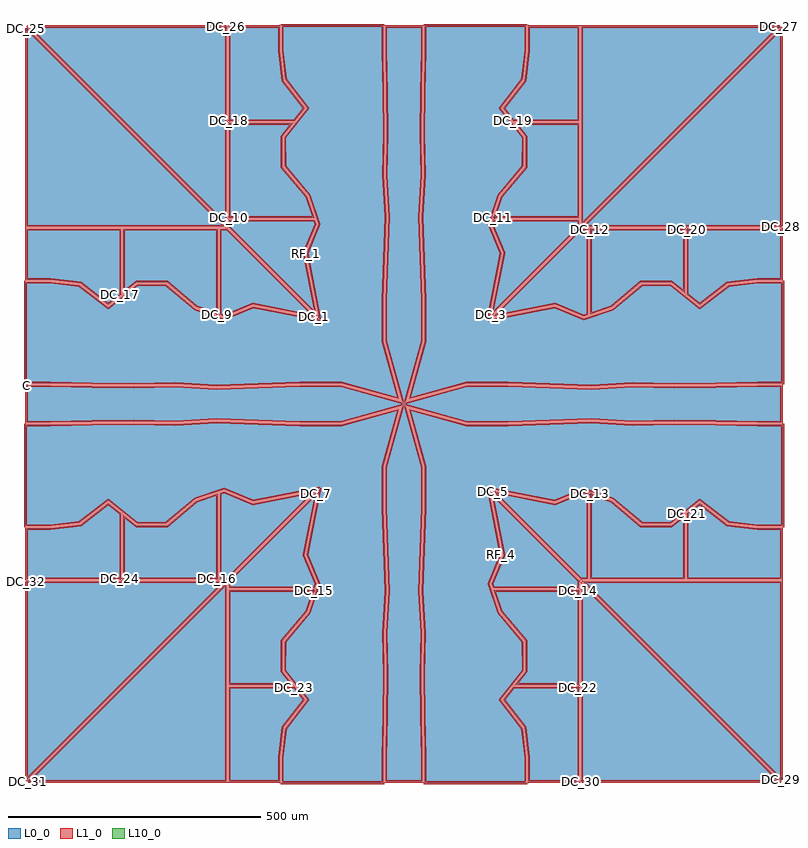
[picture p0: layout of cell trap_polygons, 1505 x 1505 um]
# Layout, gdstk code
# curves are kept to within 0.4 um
import gdstk
lib = gdstk.Library(unit=1e-6, precision=1e-09)
def P(c, l, *ps):  # polygons
    for p in ps: c.add(gdstk.Polygon(p, *l))
L0_0 = (0, 0)
L1_0 = (1, 0)
L10_0 = (10, 0)

trap_polygons = lib.new_cell('trap_polygons')
P(trap_polygons, L0_0, [(-747.5,-351.5),(-355.036,-351.5),(-747.5,-743.964),(-747.5,-351.5)],
  [(-743.964,-747.5),(-351.5,-355.036),(-351.5,-747.5),(-743.964,-747.5)],
  [(351.5,-747.5),(351.5,-355.036),(743.964,-747.5),(351.5,-747.5)],
  [(747.5,-743.964),(355.036,-351.5),(747.5,-351.5),(747.5,-743.964)],
  [(747.5,351.5),(355.036,351.5),(747.5,743.964),(747.5,351.5)],
  [(743.964,747.5),(351.5,355.036),(351.5,747.5),(743.964,747.5)],
  [(-351.5,747.5),(-351.5,355.036),(-743.964,747.5),(-351.5,747.5)],
  [(-747.5,743.964),(-355.036,351.5),(-747.5,351.5),(-747.5,743.964)],
  [(-560.758,-346.5),(-585.43,-346.5),(-640.552,-346.5),(-699.496,-346.5),(-747.5,-346.5),(-747.5,-246.5),(-699.496,-246.5),(-640.552,-239.492),(-585.43,-196.951),(-560.758,-216.68),(-560.758,-346.5)],
  [(-216.68,-560.758),(-196.951,-585.43),(-239.492,-640.552),(-246.5,-699.496),(-246.5,-747.5),(-346.5,-747.5),(-346.5,-699.496),(-346.5,-640.552),(-346.5,-585.43),(-346.5,-560.758),(-216.68,-560.758)],
  [(346.5,-560.758),(346.5,-585.43),(346.5,-640.552),(346.5,-699.496),(346.5,-747.5),(246.5,-747.5),(246.5,-699.496),(239.492,-640.552),(196.951,-585.43),(216.68,-560.758),(346.5,-560.758)],
  [(560.758,-216.68),(585.43,-196.951),(640.552,-239.492),(699.496,-246.5),(747.5,-246.5),(747.5,-346.5),(699.496,-346.5),(640.552,-346.5),(585.43,-346.5),(560.758,-346.5),(560.758,-216.68)],
  [(560.758,346.5),(585.43,346.5),(640.552,346.5),(699.496,346.5),(747.5,346.5),(747.5,246.5),(699.496,246.5),(640.552,239.492),(585.43,196.951),(560.758,216.68),(560.758,346.5)],
  [(216.68,560.758),(196.951,585.43),(239.492,640.552),(246.5,699.496),(246.5,747.5),(346.5,747.5),(346.5,699.496),(346.5,640.552),(346.5,585.43),(346.5,560.758),(216.68,560.758)],
  [(-346.5,560.758),(-346.5,585.43),(-346.5,640.552),(-346.5,699.496),(-346.5,747.5),(-246.5,747.5),(-246.5,699.496),(-239.492,640.552),(-196.951,585.43),(-216.68,560.758),(-346.5,560.758)],
  [(-560.758,216.68),(-585.43,196.951),(-640.552,239.492),(-699.496,246.5),(-747.5,246.5),(-747.5,346.5),(-699.496,346.5),(-640.552,346.5),(-585.43,346.5),(-560.758,346.5),(-560.758,216.68)],
  [(-369.015,-346.5),(-410.94,-346.5),(-468.92,-346.5),(-529.805,-346.5),(-555.758,-346.5),(-555.758,-220.679),(-529.805,-241.432),(-468.92,-241.136),(-410.94,-192.501),(-369.015,-178.208),(-369.015,-346.5)],
  [(-178.208,-369.015),(-192.501,-410.94),(-241.136,-468.92),(-241.432,-529.805),(-220.679,-555.758),(-346.5,-555.758),(-346.5,-529.805),(-346.5,-468.92),(-346.5,-410.94),(-346.5,-369.015),(-178.208,-369.015)],
  [(346.5,-369.015),(346.5,-410.94),(346.5,-468.92),(346.5,-529.805),(346.5,-555.758),(220.679,-555.758),(241.432,-529.805),(241.136,-468.92),(192.501,-410.94),(178.208,-369.015),(346.5,-369.015)],
  [(369.015,-178.208),(410.94,-192.501),(468.92,-241.136),(529.805,-241.432),(555.758,-220.679),(555.758,-346.5),(529.805,-346.5),(468.92,-346.5),(410.94,-346.5),(369.015,-346.5),(369.015,-178.208)],
  [(369.015,346.5),(410.94,346.5),(468.92,346.5),(529.805,346.5),(555.758,346.5),(555.758,220.679),(529.805,241.432),(468.92,241.136),(410.94,192.501),(369.015,178.208),(369.015,346.5)],
  [(178.208,369.015),(192.501,410.94),(241.136,468.92),(241.432,529.805),(220.679,555.758),(346.5,555.758),(346.5,529.805),(346.5,468.92),(346.5,410.94),(346.5,369.015),(178.208,369.015)],
  [(-346.5,369.015),(-346.5,410.94),(-346.5,468.92),(-346.5,529.805),(-346.5,555.758),(-220.679,555.758),(-241.432,529.805),(-241.136,468.92),(-192.501,410.94),(-178.208,369.015),(-346.5,369.015)],
  [(-369.015,178.208),(-410.94,192.501),(-468.92,241.136),(-529.805,241.432),(-555.758,220.679),(-555.758,346.5),(-529.805,346.5),(-468.92,346.5),(-410.94,346.5),(-369.015,346.5),(-369.015,178.208)],
  [(-350.036,-346.5),(-356.299,-346.5),(-364.015,-346.5),(-364.015,-176.503),(-356.299,-173.873),(-299.337,-197.523),(-177.273,-173.737),(-350.036,-346.5)],
  [(-173.737,-177.273),(-197.523,-299.337),(-173.873,-356.299),(-176.503,-364.015),(-346.5,-364.015),(-346.5,-356.299),(-346.5,-350.036),(-173.737,-177.273)],
  [(346.5,-350.036),(346.5,-356.299),(346.5,-364.015),(176.503,-364.015),(173.873,-356.299),(197.523,-299.337),(173.737,-177.273),(346.5,-350.036)],
  [(177.273,-173.737),(299.337,-197.523),(356.299,-173.873),(364.015,-176.503),(364.015,-346.5),(356.299,-346.5),(350.036,-346.5),(177.273,-173.737)],
  [(350.036,346.5),(356.299,346.5),(364.015,346.5),(364.015,176.503),(356.299,173.873),(299.337,197.523),(177.273,173.737),(350.036,346.5)],
  [(173.737,177.273),(197.523,299.337),(173.873,356.299),(176.503,364.015),(346.5,364.015),(346.5,356.299),(346.5,350.036),(173.737,177.273)],
  [(-346.5,350.036),(-346.5,356.299),(-346.5,364.015),(-176.503,364.015),(-173.873,356.299),(-197.523,299.337),(-173.737,177.273),(-346.5,350.036)],
  [(-177.273,173.737),(-299.337,197.523),(-356.299,173.873),(-364.015,176.503),(-364.015,346.5),(-356.299,346.5),(-350.036,346.5),(-177.273,173.737)],
  [(-747.5,36.5),(-700,36.5),(-535.361,33.673),(-453.158,35.298),(-370.806,30.519),(-206.032,36.5),(-124.492,36.5),(-2.831,2.831),(-36.5,124.492),(-36.5,206.032),(-30.519,370.806),(-35.298,453.158),(-33.673,535.361),(-36.5,700),(-36.5,747.5),(36.5,747.5),(36.5,700),(33.673,535.361),(35.298,453.158),(30.519,370.806),(36.5,206.032),(36.5,124.492),(2.831,2.831),(124.492,36.5),(206.032,36.5),(370.806,30.519),(453.158,35.298),(535.361,33.673),(700,36.5),(747.5,36.5),(747.5,-36.5),(700,-36.5),(535.361,-33.673),(453.158,-35.298),(370.806,-30.519),(206.032,-36.5),(124.492,-36.5),(2.831,-2.831),(36.5,-124.492),(36.5,-206.032),(30.519,-370.806),(35.298,-453.158),(33.673,-535.361),(36.5,-700),(36.5,-747.5),(-36.5,-747.5),(-36.5,-700),(-33.673,-535.361),(-35.298,-453.158),(-30.519,-370.806),(-36.5,-206.032),(-36.5,-124.492),(-2.831,-2.831),(-124.492,-36.5),(-206.032,-36.5),(-370.806,-30.519),(-453.158,-35.298),(-535.361,-33.673),(-700,-36.5),(-747.5,-36.5)],
  [(192.327,-298.812),(168.531,-356.125),(188.07,-413.437),(236.144,-470.75),(236.423,-528.062),(190.593,-585.375),(234.824,-642.687),(241.5,-700),(241.5,-750),(41.5,-750),(41.5,-700),(38.674,-535.375),(40.301,-453.062),(35.524,-370.75),(41.5,-206.125),(41.5,-123.812),(10.004,-10.004),(123.812,-41.5),(206.125,-41.5),(370.75,-35.524),(453.062,-40.301),(535.375,-38.674),(700,-41.5),(750,-41.5),(750,-241.5),(700,-241.5),(642.687,-234.824),(585.375,-190.593),(528.062,-236.423),(470.75,-236.144),(413.437,-188.07),(356.125,-168.531),(298.812,-192.327),(166.555,-166.555)],
  [(166.555,166.555),(298.812,192.327),(356.125,168.531),(413.437,188.07),(470.75,236.144),(528.062,236.423),(585.375,190.593),(642.687,234.824),(700,241.5),(750,241.5),(750,41.5),(700,41.5),(535.375,38.674),(453.062,40.301),(370.75,35.524),(206.125,41.5),(123.812,41.5),(10.004,10.004),(41.5,123.812),(41.5,206.125),(35.524,370.75),(40.301,453.062),(38.674,535.375),(41.5,700),(41.5,750),(241.5,750),(241.5,700),(234.824,642.687),(190.593,585.375),(236.423,528.062),(236.144,470.75),(188.07,413.437),(168.531,356.125),(192.327,298.812)],
  [(-166.555,-166.555),(-298.812,-192.327),(-356.125,-168.531),(-413.437,-188.07),(-470.75,-236.144),(-528.062,-236.423),(-585.375,-190.593),(-642.687,-234.824),(-700,-241.5),(-750,-241.5),(-750,-41.5),(-700,-41.5),(-535.375,-38.674),(-453.062,-40.301),(-370.75,-35.524),(-206.125,-41.5),(-123.812,-41.5),(-10.004,-10.004),(-41.5,-123.812),(-41.5,-206.125),(-35.524,-370.75),(-40.301,-453.062),(-38.674,-535.375),(-41.5,-700),(-41.5,-750),(-241.5,-750),(-241.5,-700),(-234.824,-642.687),(-190.593,-585.375),(-236.423,-528.062),(-236.144,-470.75),(-188.07,-413.437),(-168.531,-356.125),(-192.327,-298.812)],
  [(-192.327,298.812),(-168.531,356.125),(-188.07,413.437),(-236.144,470.75),(-236.423,528.062),(-190.593,585.375),(-234.824,642.687),(-241.5,700),(-241.5,750),(-41.5,750),(-41.5,700),(-38.674,535.375),(-40.301,453.062),(-35.524,370.75),(-41.5,206.125),(-41.5,123.812),(-10.004,10.004),(-123.812,41.5),(-206.125,41.5),(-370.75,35.524),(-453.062,40.301),(-535.375,38.674),(-700,41.5),(-750,41.5),(-750,241.5),(-700,241.5),(-642.687,234.824),(-585.375,190.593),(-528.062,236.423),(-470.75,236.144),(-413.437,188.07),(-356.125,168.531),(-298.812,192.327),(-166.555,166.555)])
P(trap_polygons, L1_0, [(-747.5,-349),(-747.5,-354),(-361.071,-354),(-745,-737.929),(-745,-351.5),(-750,-351.5),(-750,-746.464),(-747.5,-747.5),(-351.5,-351.5),(-352.536,-349)],
  [(-745.732,-745.732),(-742.197,-749.268),(-354,-361.071),(-354,-745),(-743.964,-745),(-743.964,-750),(-349,-750),(-349,-352.536),(-351.5,-351.5)],
  [(349,-747.5),(354,-747.5),(354,-361.071),(737.929,-745),(351.5,-745),(351.5,-750),(746.464,-750),(747.5,-747.5),(351.5,-351.5),(349,-352.536)],
  [(745.732,-745.732),(749.268,-742.197),(361.071,-354),(745,-354),(745,-743.964),(750,-743.964),(750,-349),(352.536,-349),(351.5,-351.5)],
  [(747.5,349),(747.5,354),(361.071,354),(745,737.929),(745,351.5),(750,351.5),(750,746.464),(747.5,747.5),(351.5,351.5),(352.536,349)],
  [(745.732,745.732),(742.197,749.268),(354,361.071),(354,745),(743.964,745),(743.964,750),(349,750),(349,352.536),(351.5,351.5)],
  [(-349,747.5),(-354,747.5),(-354,361.071),(-737.929,745),(-351.5,745),(-351.5,750),(-746.464,750),(-747.5,747.5),(-351.5,351.5),(-349,352.536)],
  [(-745.732,745.732),(-749.268,742.197),(-361.071,354),(-745,354),(-745,743.964),(-750,743.964),(-750,349),(-352.536,349),(-351.5,351.5)],
  [(-560.758,-349),(-560.758,-344),(-745,-344),(-745,-249),(-699.348,-249),(-639.571,-241.893),(-585.457,-200.13),(-563.258,-217.882),(-563.258,-346.5),(-558.258,-346.5),(-558.258,-215.478),(-585.402,-193.772),(-641.533,-237.091),(-699.644,-244),(-750,-244),(-750,-349)],
  [(-214.728,-559.196),(-218.633,-562.319),(-200.13,-585.457),(-241.893,-639.571),(-249,-699.348),(-249,-745),(-344,-745),(-344,-563.258),(-216.68,-563.258),(-216.68,-558.258),(-349,-558.258),(-349,-750),(-244,-750),(-244,-699.644),(-237.091,-641.533),(-193.772,-585.402)],
  [(349,-560.758),(344,-560.758),(344,-745),(249,-745),(249,-699.348),(241.893,-639.571),(200.13,-585.457),(217.882,-563.258),(346.5,-563.258),(346.5,-558.258),(215.478,-558.258),(193.772,-585.402),(237.091,-641.533),(244,-699.644),(244,-750),(349,-750)],
  [(559.196,-214.728),(562.319,-218.633),(585.457,-200.13),(639.571,-241.893),(699.348,-249),(745,-249),(745,-344),(563.258,-344),(563.258,-216.68),(558.258,-216.68),(558.258,-349),(750,-349),(750,-244),(699.644,-244),(641.533,-237.091),(585.402,-193.772)],
  [(560.758,349),(560.758,344),(745,344),(745,249),(699.348,249),(639.571,241.893),(585.457,200.13),(563.258,217.882),(563.258,346.5),(558.258,346.5),(558.258,215.478),(585.402,193.772),(641.533,237.091),(699.644,244),(750,244),(750,349)],
  [(214.728,559.196),(218.633,562.319),(200.13,585.457),(241.893,639.571),(249,699.348),(249,745),(344,745),(344,563.258),(216.68,563.258),(216.68,558.258),(349,558.258),(349,750),(244,750),(244,699.644),(237.091,641.533),(193.772,585.402)],
  [(-349,560.758),(-344,560.758),(-344,745),(-249,745),(-249,699.348),(-241.893,639.571),(-200.13,585.457),(-217.882,563.258),(-346.5,563.258),(-346.5,558.258),(-215.478,558.258),(-193.772,585.402),(-237.091,641.533),(-244,699.644),(-244,750),(-349,750)],
  [(-559.196,214.728),(-562.319,218.633),(-585.457,200.13),(-639.571,241.893),(-699.348,249),(-745,249),(-745,344),(-563.258,344),(-563.258,216.68),(-558.258,216.68),(-558.258,349),(-750,349),(-750,244),(-699.644,244),(-641.533,237.091),(-585.402,193.772)],
  [(-369.015,-349),(-369.015,-344),(-553.258,-344),(-553.258,-225.879),(-530.676,-243.936),(-468.005,-243.631),(-409.691,-194.717),(-371.515,-181.702),(-371.515,-346.5),(-366.515,-346.5),(-366.515,-175.708),(-367.456,-175.035),(-412.189,-190.286),(-469.835,-238.64),(-528.934,-238.927),(-556.149,-217.165),(-558.258,-218.179),(-558.258,-349)],
  [(-175.842,-369.822),(-180.574,-368.209),(-194.717,-409.691),(-243.631,-468.005),(-243.936,-530.676),(-225.879,-553.258),(-344,-553.258),(-344,-371.515),(-178.208,-371.515),(-178.208,-366.515),(-349,-366.515),(-349,-558.258),(-218.179,-558.258),(-217.165,-556.149),(-238.927,-528.934),(-238.64,-469.835),(-190.286,-412.189)],
  [(349,-369.015),(344,-369.015),(344,-553.258),(225.879,-553.258),(243.936,-530.676),(243.631,-468.005),(194.717,-409.691),(181.702,-371.515),(346.5,-371.515),(346.5,-366.515),(175.708,-366.515),(175.035,-367.456),(190.286,-412.189),(238.64,-469.835),(238.927,-528.934),(217.165,-556.149),(218.179,-558.258),(349,-558.258)],
  [(369.822,-175.842),(368.209,-180.574),(409.691,-194.717),(468.005,-243.631),(530.676,-243.936),(553.258,-225.879),(553.258,-344),(371.515,-344),(371.515,-178.208),(366.515,-178.208),(366.515,-349),(558.258,-349),(558.258,-218.179),(556.149,-217.165),(528.934,-238.927),(469.835,-238.64),(412.189,-190.286)],
  [(369.015,349),(369.015,344),(553.258,344),(553.258,225.879),(530.676,243.936),(468.005,243.631),(409.691,194.717),(371.515,181.702),(371.515,346.5),(366.515,346.5),(366.515,175.708),(367.456,175.035),(412.189,190.286),(469.835,238.64),(528.934,238.927),(556.149,217.165),(558.258,218.179),(558.258,349)],
  [(175.842,369.822),(180.574,368.209),(194.717,409.691),(243.631,468.005),(243.936,530.676),(225.879,553.258),(344,553.258),(344,371.515),(178.208,371.515),(178.208,366.515),(349,366.515),(349,558.258),(218.179,558.258),(217.165,556.149),(238.927,528.934),(238.64,469.835),(190.286,412.189)],
  [(-349,369.015),(-344,369.015),(-344,553.258),(-225.879,553.258),(-243.936,530.676),(-243.631,468.005),(-194.717,409.691),(-181.702,371.515),(-346.5,371.515),(-346.5,366.515),(-175.708,366.515),(-175.035,367.456),(-190.286,412.189),(-238.64,469.835),(-238.927,528.934),(-217.165,556.149),(-218.179,558.258),(-349,558.258)],
  [(-369.822,175.842),(-368.209,180.574),(-409.691,194.717),(-468.005,243.631),(-530.676,243.936),(-553.258,225.879),(-553.258,344),(-371.515,344),(-371.515,178.208),(-366.515,178.208),(-366.515,349),(-558.258,349),(-558.258,218.179),(-556.149,217.165),(-528.934,238.927),(-469.835,238.64),(-412.189,190.286)],
  [(-350.036,-349),(-350.036,-344),(-361.515,-344),(-361.515,-178.292),(-356.385,-176.543),(-299.599,-200.121),(-184.828,-177.757),(-351.803,-344.732),(-348.268,-348.268),(-173.737,-173.737),(-175.297,-170.805),(-299.075,-194.925),(-356.212,-171.202),(-366.515,-174.714),(-366.515,-349)],
  [(-171.284,-177.751),(-176.191,-176.795),(-200.121,-299.599),(-176.543,-356.385),(-178.292,-361.515),(-344,-361.515),(-344,-351.071),(-171.97,-179.041),(-175.505,-175.505),(-349,-349),(-349,-366.515),(-174.714,-366.515),(-171.202,-356.212),(-194.925,-299.075)],
  [(349,-350.036),(344,-350.036),(344,-361.515),(178.292,-361.515),(176.543,-356.385),(200.121,-299.599),(177.757,-184.828),(344.732,-351.803),(348.268,-348.268),(173.737,-173.737),(170.805,-175.297),(194.925,-299.075),(171.202,-356.212),(174.714,-366.515),(349,-366.515)],
  [(177.751,-171.284),(176.795,-176.191),(299.599,-200.121),(356.385,-176.543),(361.515,-178.292),(361.515,-344),(351.071,-344),(179.041,-171.97),(175.505,-175.505),(349,-349),(366.515,-349),(366.515,-174.714),(356.212,-171.202),(299.075,-194.925)],
  [(350.036,349),(350.036,344),(361.515,344),(361.515,178.292),(356.385,176.543),(299.599,200.121),(184.828,177.757),(351.803,344.732),(348.268,348.268),(173.737,173.737),(175.297,170.805),(299.075,194.925),(356.212,171.202),(366.515,174.714),(366.515,349)],
  [(171.284,177.751),(176.191,176.795),(200.121,299.599),(176.543,356.385),(178.292,361.515),(344,361.515),(344,351.071),(171.97,179.041),(175.505,175.505),(349,349),(349,366.515),(174.714,366.515),(171.202,356.212),(194.925,299.075)],
  [(-349,350.036),(-344,350.036),(-344,361.515),(-178.292,361.515),(-176.543,356.385),(-200.121,299.599),(-177.757,184.828),(-344.732,351.803),(-348.268,348.268),(-173.737,173.737),(-170.805,175.297),(-194.925,299.075),(-171.202,356.212),(-174.714,366.515),(-349,366.515)],
  [(-177.751,171.284),(-176.795,176.191),(-299.599,200.121),(-356.385,176.543),(-361.515,178.292),(-361.515,344),(-351.071,344),(-179.041,171.97),(-175.505,175.505),(-349,349),(-366.515,349),(-366.515,174.714),(-356.212,171.202),(-299.075,194.925)],
  [(-747.5,39),(-747.5,34),(-700.025,34),(-535.354,31.173),(-453.206,32.797),(-370.835,28.016),(-205.986,34),(-124.831,34),(-1.089,-0.245),(0.245,1.089),(-34,124.831),(-34,205.986),(-28.016,370.835),(-32.797,453.206),(-31.173,535.354),(-34,700.025),(-34,745),(34,745),(34,700.025),(31.173,535.354),(32.797,453.206),(28.016,370.835),(34,205.986),(34,124.831),(-0.245,1.089),(1.089,-0.245),(124.831,34),(205.986,34),(370.835,28.016),(453.206,32.797),(535.354,31.173),(700.025,34),(745,34),(745,-34),(700.025,-34),(535.354,-31.173),(453.206,-32.797),(370.835,-28.016),(205.986,-34),(124.831,-34),(1.089,0.245),(-0.245,-1.089),(34,-124.831),(34,-205.986),(28.016,-370.835),(32.797,-453.206),(31.173,-535.354),(34,-700.025),(34,-745),(-34,-745),(-34,-700.025),(-31.173,-535.354),(-32.797,-453.206),(-28.016,-370.835),(-34,-205.986),(-34,-124.831),(0.245,-1.089),(-1.089,0.245),(-124.831,-34),(-205.986,-34),(-370.835,-28.016),(-453.206,-32.797),(-535.354,-31.173),(-700.025,-34),(-745,-34),(-745,36.5),(-750,36.5),(-750,-39),(-699.975,-39),(-535.368,-36.173),(-453.11,-37.8),(-370.778,-33.022),(-206.079,-39),(-124.152,-39),(-6.418,-6.418),(-39,-124.152),(-39,-206.079),(-33.022,-370.778),(-37.8,-453.11),(-36.173,-535.368),(-39,-699.975),(-39,-750),(39,-750),(39,-699.975),(36.173,-535.368),(37.8,-453.11),(33.022,-370.778),(39,-206.079),(39,-124.152),(6.418,-6.418),(124.152,-39),(206.079,-39),(370.778,-33.022),(453.11,-37.8),(535.368,-36.173),(699.975,-39),(750,-39),(750,39),(699.975,39),(535.368,36.173),(453.11,37.8),(370.778,33.022),(206.079,39),(124.152,39),(6.418,6.418),(39,124.152),(39,206.079),(33.022,370.778),(37.8,453.11),(36.173,535.368),(39,699.975),(39,750),(-39,750),(-39,699.975),(-36.173,535.368),(-37.8,453.11),(-33.022,370.778),(-39,206.079),(-39,124.152),(-6.418,6.418),(-124.152,39),(-206.079,39),(-370.778,33.022),(-453.11,37.8),(-535.368,36.173),(-699.975,39)],
  [(194.636,-299.771),(190.018,-297.854),(165.86,-356.038),(185.855,-414.686),(233.649,-471.665),(233.919,-527.191),(187.414,-585.348),(232.421,-643.666),(239,-700.145),(239,-747.5),(44,-747.5),(44,-699.975),(41.174,-535.382),(42.802,-453.015),(38.027,-370.722),(44,-206.171),(44,-123.473),(13.591,-13.591),(123.473,-44),(206.171,-44),(370.722,-38.027),(453.015,-42.802),(535.382,-41.174),(699.975,-44),(747.5,-44),(747.5,-239),(700.145,-239),(643.666,-232.421),(585.348,-187.414),(527.191,-233.919),(471.665,-233.649),(414.686,-185.855),(356.038,-165.86),(298.55,-189.729),(164.579,-163.623),(163.623,-164.579),(189.873,-299.291),(194.781,-298.334),(169.718,-169.718),(299.075,-194.925),(356.212,-171.202),(412.189,-190.286),(469.835,-238.64),(528.934,-238.927),(585.402,-193.772),(641.709,-237.227),(699.855,-244),(752.5,-244),(752.5,-39),(700.025,-39),(535.368,-36.173),(453.11,-37.8),(370.778,-33.022),(206.079,-39),(124.152,-39),(8.262,-6.928),(6.928,-8.262),(39,-124.152),(39,-206.079),(33.022,-370.778),(37.8,-453.11),(36.173,-535.368),(39,-700.025),(39,-752.5),(244,-752.5),(244,-699.855),(237.227,-641.709),(193.772,-585.402),(238.927,-528.934),(238.64,-469.835),(190.286,-412.189),(171.202,-356.212)],
  [(166.077,169.009),(167.033,164.101),(298.55,189.729),(356.038,165.86),(414.686,185.855),(471.665,233.649),(527.191,233.919),(585.348,187.414),(643.666,232.421),(700.145,239),(747.5,239),(747.5,44),(699.975,44),(535.382,41.174),(453.015,42.802),(370.722,38.027),(206.171,44),(123.473,44),(13.591,13.591),(44,123.473),(44,206.171),(38.027,370.722),(42.802,453.015),(41.174,535.382),(44,699.975),(44,747.5),(239,747.5),(239,700.145),(232.421,643.666),(187.414,585.348),(233.919,527.191),(233.649,471.665),(185.855,414.686),(165.86,356.038),(189.729,298.55),(164.101,167.033),(169.009,166.077),(194.925,299.075),(171.202,356.212),(190.286,412.189),(238.64,469.835),(238.927,528.934),(193.772,585.402),(237.227,641.709),(244,699.855),(244,752.5),(39,752.5),(39,700.025),(36.173,535.368),(37.8,453.11),(33.022,370.778),(39,206.079),(39,124.152),(6.928,8.262),(8.262,6.928),(124.152,39),(206.079,39),(370.778,33.022),(453.11,37.8),(535.368,36.173),(700.025,39),(752.5,39),(752.5,244),(699.855,244),(641.709,237.227),(585.402,193.772),(528.934,238.927),(469.835,238.64),(412.189,190.286),(356.212,171.202),(299.075,194.925)],
  [(-166.077,-169.009),(-167.033,-164.101),(-298.55,-189.729),(-356.038,-165.86),(-414.686,-185.855),(-471.665,-233.649),(-527.191,-233.919),(-585.348,-187.414),(-643.666,-232.421),(-700.145,-239),(-747.5,-239),(-747.5,-44),(-699.975,-44),(-535.382,-41.174),(-453.015,-42.802),(-370.722,-38.027),(-206.171,-44),(-123.473,-44),(-13.591,-13.591),(-44,-123.473),(-44,-206.171),(-38.027,-370.722),(-42.802,-453.015),(-41.174,-535.382),(-44,-699.975),(-44,-747.5),(-239,-747.5),(-239,-700.145),(-232.421,-643.666),(-187.414,-585.348),(-233.919,-527.191),(-233.649,-471.665),(-185.855,-414.686),(-165.86,-356.038),(-189.729,-298.55),(-164.101,-167.033),(-169.009,-166.077),(-194.925,-299.075),(-171.202,-356.212),(-190.286,-412.189),(-238.64,-469.835),(-238.927,-528.934),(-193.772,-585.402),(-237.227,-641.709),(-244,-699.855),(-244,-752.5),(-39,-752.5),(-39,-700.025),(-36.173,-535.368),(-37.8,-453.11),(-33.022,-370.778),(-39,-206.079),(-39,-124.152),(-6.928,-8.262),(-8.262,-6.928),(-124.152,-39),(-206.079,-39),(-370.778,-33.022),(-453.11,-37.8),(-535.368,-36.173),(-700.025,-39),(-752.5,-39),(-752.5,-244),(-699.855,-244),(-641.709,-237.227),(-585.402,-193.772),(-528.934,-238.927),(-469.835,-238.64),(-412.189,-190.286),(-356.212,-171.202),(-299.075,-194.925)],
  [(-194.636,299.771),(-190.018,297.854),(-165.86,356.038),(-185.855,414.686),(-233.649,471.665),(-233.919,527.191),(-187.414,585.348),(-232.421,643.666),(-239,700.145),(-239,747.5),(-44,747.5),(-44,699.975),(-41.174,535.382),(-42.802,453.015),(-38.027,370.722),(-44,206.171),(-44,123.473),(-13.591,13.591),(-123.473,44),(-206.171,44),(-370.722,38.027),(-453.015,42.802),(-535.382,41.174),(-699.975,44),(-747.5,44),(-747.5,239),(-700.145,239),(-643.666,232.421),(-585.348,187.414),(-527.191,233.919),(-471.665,233.649),(-414.686,185.855),(-356.038,165.86),(-298.55,189.729),(-164.579,163.623),(-163.623,164.579),(-189.873,299.291),(-194.781,298.334),(-169.718,169.718),(-299.075,194.925),(-356.212,171.202),(-412.189,190.286),(-469.835,238.64),(-528.934,238.927),(-585.402,193.772),(-641.709,237.227),(-699.855,244),(-752.5,244),(-752.5,39),(-700.025,39),(-535.368,36.173),(-453.11,37.8),(-370.778,33.022),(-206.079,39),(-124.152,39),(-8.262,6.928),(-6.928,8.262),(-39,124.152),(-39,206.079),(-33.022,370.778),(-37.8,453.11),(-36.173,535.368),(-39,700.025),(-39,752.5),(-244,752.5),(-244,699.855),(-237.227,641.709),(-193.772,585.402),(-238.927,528.934),(-238.64,469.835),(-190.286,412.189),(-171.202,356.212)])
P(trap_polygons, L10_0, [(0,0),(0,0),(0,0),(0,0)])
trap_polygons.add(gdstk.Label('DC_32', (-747.5,-351.5), layer=2, texttype=0))
trap_polygons.add(gdstk.Label('DC_31', (-743.964,-747.5), layer=2, texttype=0))
trap_polygons.add(gdstk.Label('DC_30', (351.5,-747.5), layer=2, texttype=0))
trap_polygons.add(gdstk.Label('DC_29', (747.5,-743.964), layer=2, texttype=0))
trap_polygons.add(gdstk.Label('DC_28', (747.5,351.5), layer=2, texttype=0))
trap_polygons.add(gdstk.Label('DC_27', (743.964,747.5), layer=2, texttype=0))
trap_polygons.add(gdstk.Label('DC_26', (-351.5,747.5), layer=2, texttype=0))
trap_polygons.add(gdstk.Label('DC_25', (-747.5,743.964), layer=2, texttype=0))
trap_polygons.add(gdstk.Label('DC_24', (-560.758,-346.5), layer=2, texttype=0))
trap_polygons.add(gdstk.Label('DC_23', (-216.68,-560.758), layer=2, texttype=0))
trap_polygons.add(gdstk.Label('DC_22', (346.5,-560.758), layer=2, texttype=0))
trap_polygons.add(gdstk.Label('DC_21', (560.758,-216.68), layer=2, texttype=0))
trap_polygons.add(gdstk.Label('DC_20', (560.758,346.5), layer=2, texttype=0))
trap_polygons.add(gdstk.Label('DC_19', (216.68,560.758), layer=2, texttype=0))
trap_polygons.add(gdstk.Label('DC_18', (-346.5,560.758), layer=2, texttype=0))
trap_polygons.add(gdstk.Label('DC_17', (-560.758,216.68), layer=2, texttype=0))
trap_polygons.add(gdstk.Label('DC_16', (-369.015,-346.5), layer=2, texttype=0))
trap_polygons.add(gdstk.Label('DC_15', (-178.208,-369.015), layer=2, texttype=0))
trap_polygons.add(gdstk.Label('DC_14', (346.5,-369.015), layer=2, texttype=0))
trap_polygons.add(gdstk.Label('DC_13', (369.015,-178.208), layer=2, texttype=0))
trap_polygons.add(gdstk.Label('DC_12', (369.015,346.5), layer=2, texttype=0))
trap_polygons.add(gdstk.Label('DC_11', (178.208,369.015), layer=2, texttype=0))
trap_polygons.add(gdstk.Label('DC_10', (-346.5,369.015), layer=2, texttype=0))
trap_polygons.add(gdstk.Label('DC_9', (-369.015,178.208), layer=2, texttype=0))
trap_polygons.add(gdstk.Label('DC_8', (-350.036,-346.5), layer=2, texttype=0))
trap_polygons.add(gdstk.Label('DC_7', (-173.737,-177.273), layer=2, texttype=0))
trap_polygons.add(gdstk.Label('DC_6', (346.5,-350.036), layer=2, texttype=0))
trap_polygons.add(gdstk.Label('DC_5', (177.273,-173.737), layer=2, texttype=0))
trap_polygons.add(gdstk.Label('DC_4', (350.036,346.5), layer=2, texttype=0))
trap_polygons.add(gdstk.Label('DC_3', (173.737,177.273), layer=2, texttype=0))
trap_polygons.add(gdstk.Label('DC_2', (-346.5,350.036), layer=2, texttype=0))
trap_polygons.add(gdstk.Label('DC_1', (-177.273,173.737), layer=2, texttype=0))
trap_polygons.add(gdstk.Label('C', (-747.5,36.5), layer=2, texttype=0))
trap_polygons.add(gdstk.Label('RF_4', (192.327,-298.812), layer=2, texttype=0))
trap_polygons.add(gdstk.Label('RF_3', (166.555,166.555), layer=2, texttype=0))
trap_polygons.add(gdstk.Label('RF_2', (-166.555,-166.555), layer=2, texttype=0))
trap_polygons.add(gdstk.Label('RF_1', (-192.327,298.812), layer=2, texttype=0))

lib.write_gds('trap_polygons.gds')
